VERSION 5.8 ;
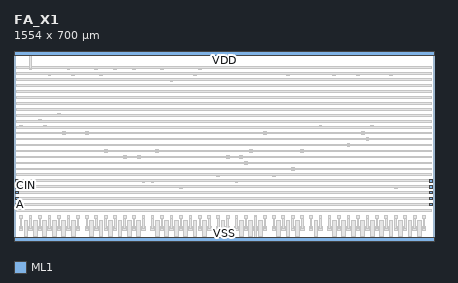
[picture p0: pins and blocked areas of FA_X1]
MACRO FA_X1
  CLASS CORE ;
  ORIGIN 0 0 ;
  SIZE 1554 BY 700 ;
  SITE ICPS2023_5_ROW700 ;
  PIN A
    DIRECTION INPUT ;
    USE SIGNAL ;
    PORT
      LAYER ML1 ;
        RECT 5 130 15 140 ;
        RECT 1539 130 1549 140 ;
    END
  END A
  PIN B
    DIRECTION INPUT ;
    USE SIGNAL ;
    PORT
      LAYER ML1 ;
        RECT 5 152 15 162 ;
        RECT 1539 152 1549 162 ;
    END
  END B
  PIN CIN
    DIRECTION INPUT ;
    USE SIGNAL ;
    PORT
      LAYER ML1 ;
        RECT 5 174 15 184 ;
        RECT 1539 174 1549 184 ;
    END
  END CIN
  PIN SUM
    DIRECTION OUTPUT ;
    USE SIGNAL ;
    PORT
      LAYER ML1 ;
        RECT 5 196 15 206 ;
        RECT 1539 196 1549 206 ;
    END
  END SUM
  PIN COUT
    DIRECTION OUTPUT ;
    USE SIGNAL ;
    PORT
      LAYER ML1 ;
        RECT 5 218 15 228 ;
        RECT 1539 218 1549 228 ;
    END
  END COUT
  PIN VDD
    DIRECTION INOUT ;
    USE POWER ;
    PORT
      LAYER ML1 ;
        RECT 0 688 1554 700 ;
    END
  END VDD
  PIN VSS
    DIRECTION INOUT ;
    USE GROUND ;
    PORT
      LAYER ML1 ;
        RECT 0 0 1554 12 ;
    END
  END VSS
  OBS
    LAYER ML1 ;
      RECT 20 39.5 33 52.5 ;
      RECT 55 39.5 68 52.5 ;
      RECT 90 39.5 103 52.5 ;
      RECT 125 39.5 138 52.5 ;
      RECT 160 39.5 173 52.5 ;
      RECT 195 39.5 208 52.5 ;
      RECT 230 39.5 243 52.5 ;
      RECT 37.5 16 50.5 29 ;
      RECT 37.5 63 50.5 76 ;
      RECT 37 16 51 76 ;
      RECT 72.5 16 85.5 29 ;
      RECT 72.5 63 85.5 76 ;
      RECT 72 16 86 76 ;
      RECT 107.5 16 120.5 29 ;
      RECT 107.5 63 120.5 76 ;
      RECT 107 16 121 76 ;
      RECT 142.5 16 155.5 29 ;
      RECT 142.5 63 155.5 76 ;
      RECT 142 16 156 76 ;
      RECT 177.5 16 190.5 29 ;
      RECT 177.5 63 190.5 76 ;
      RECT 177 16 191 76 ;
      RECT 212.5 16 225.5 29 ;
      RECT 212.5 63 225.5 76 ;
      RECT 212 16 226 76 ;
      RECT 23.5 46 29.5 89 ;
      RECT 21.5 84 31.5 94 ;
      RECT 21.5 416 31.5 426 ;
      RECT 58.5 46 64.5 89 ;
      RECT 56.5 84 66.5 94 ;
      RECT 56.5 636 66.5 646 ;
      RECT 93.5 46 99.5 89 ;
      RECT 91.5 84 101.5 94 ;
      RECT 91.5 438 101.5 448 ;
      RECT 128.5 46 134.5 89 ;
      RECT 126.5 84 136.5 94 ;
      RECT 126.5 614 136.5 624 ;
      RECT 163.5 46 169.5 89 ;
      RECT 161.5 84 171.5 94 ;
      RECT 161.5 460 171.5 470 ;
      RECT 198.5 46 204.5 89 ;
      RECT 196.5 84 206.5 94 ;
      RECT 196.5 636 206.5 646 ;
      RECT 233.5 46 239.5 89 ;
      RECT 231.5 84 241.5 94 ;
      RECT 231.5 526 241.5 536 ;
      RECT 39 152 49 162 ;
      RECT 74 130 84 140 ;
      RECT 109 416 119 426 ;
      RECT 144 152 154 162 ;
      RECT 179 394 189 404 ;
      RECT 214 614 224 624 ;
      RECT 263 39.5 276 52.5 ;
      RECT 298 39.5 311 52.5 ;
      RECT 333 39.5 346 52.5 ;
      RECT 368 39.5 381 52.5 ;
      RECT 403 39.5 416 52.5 ;
      RECT 438 39.5 451 52.5 ;
      RECT 473 39.5 486 52.5 ;
      RECT 280.5 16 293.5 29 ;
      RECT 280.5 63 293.5 76 ;
      RECT 280 16 294 76 ;
      RECT 315.5 16 328.5 29 ;
      RECT 315.5 63 328.5 76 ;
      RECT 315 16 329 76 ;
      RECT 350.5 16 363.5 29 ;
      RECT 350.5 63 363.5 76 ;
      RECT 350 16 364 76 ;
      RECT 385.5 16 398.5 29 ;
      RECT 385.5 63 398.5 76 ;
      RECT 385 16 399 76 ;
      RECT 420.5 16 433.5 29 ;
      RECT 420.5 63 433.5 76 ;
      RECT 420 16 434 76 ;
      RECT 455.5 16 468.5 29 ;
      RECT 455.5 63 468.5 76 ;
      RECT 455 16 469 76 ;
      RECT 266.5 46 272.5 89 ;
      RECT 264.5 84 274.5 94 ;
      RECT 264.5 394 274.5 404 ;
      RECT 301.5 46 307.5 89 ;
      RECT 299.5 84 309.5 94 ;
      RECT 299.5 636 309.5 646 ;
      RECT 336.5 46 342.5 89 ;
      RECT 334.5 84 344.5 94 ;
      RECT 334.5 328 344.5 338 ;
      RECT 371.5 46 377.5 89 ;
      RECT 369.5 84 379.5 94 ;
      RECT 369.5 636 379.5 646 ;
      RECT 406.5 46 412.5 89 ;
      RECT 404.5 84 414.5 94 ;
      RECT 404.5 306 414.5 316 ;
      RECT 441.5 46 447.5 89 ;
      RECT 439.5 84 449.5 94 ;
      RECT 439.5 636 449.5 646 ;
      RECT 476.5 46 482.5 89 ;
      RECT 474.5 84 484.5 94 ;
      RECT 474.5 218 484.5 228 ;
      RECT 282 130 292 140 ;
      RECT 317 614 327 624 ;
      RECT 352 174 362 184 ;
      RECT 387 152 397 162 ;
      RECT 422 130 432 140 ;
      RECT 457 306 467 316 ;
      RECT 506 39.5 519 52.5 ;
      RECT 541 39.5 554 52.5 ;
      RECT 576 39.5 589 52.5 ;
      RECT 611 39.5 624 52.5 ;
      RECT 646 39.5 659 52.5 ;
      RECT 681 39.5 694 52.5 ;
      RECT 716 39.5 729 52.5 ;
      RECT 523.5 16 536.5 29 ;
      RECT 523.5 63 536.5 76 ;
      RECT 523 16 537 76 ;
      RECT 558.5 16 571.5 29 ;
      RECT 558.5 63 571.5 76 ;
      RECT 558 16 572 76 ;
      RECT 593.5 16 606.5 29 ;
      RECT 593.5 63 606.5 76 ;
      RECT 593 16 607 76 ;
      RECT 628.5 16 641.5 29 ;
      RECT 628.5 63 641.5 76 ;
      RECT 628 16 642 76 ;
      RECT 663.5 16 676.5 29 ;
      RECT 663.5 63 676.5 76 ;
      RECT 663 16 677 76 ;
      RECT 698.5 16 711.5 29 ;
      RECT 698.5 63 711.5 76 ;
      RECT 698 16 712 76 ;
      RECT 509.5 46 515.5 89 ;
      RECT 507.5 84 517.5 94 ;
      RECT 507.5 218 517.5 228 ;
      RECT 544.5 46 550.5 89 ;
      RECT 542.5 84 552.5 94 ;
      RECT 542.5 636 552.5 646 ;
      RECT 579.5 46 585.5 89 ;
      RECT 577.5 84 587.5 94 ;
      RECT 577.5 592 587.5 602 ;
      RECT 614.5 46 620.5 89 ;
      RECT 612.5 84 622.5 94 ;
      RECT 612.5 196 622.5 206 ;
      RECT 649.5 46 655.5 89 ;
      RECT 647.5 84 657.5 94 ;
      RECT 647.5 570 657.5 580 ;
      RECT 684.5 46 690.5 89 ;
      RECT 682.5 84 692.5 94 ;
      RECT 682.5 636 692.5 646 ;
      RECT 719.5 46 725.5 89 ;
      RECT 717.5 84 727.5 94 ;
      RECT 717.5 548 727.5 558 ;
      RECT 525 328 535 338 ;
      RECT 560 526 570 536 ;
      RECT 595 174 605 184 ;
      RECT 630 548 640 558 ;
      RECT 665 614 675 624 ;
      RECT 700 174 710 184 ;
      RECT 749 39.5 762 52.5 ;
      RECT 784 39.5 797 52.5 ;
      RECT 766.5 16 779.5 29 ;
      RECT 766.5 63 779.5 76 ;
      RECT 766 16 780 76 ;
      RECT 752.5 46 758.5 89 ;
      RECT 750.5 84 760.5 94 ;
      RECT 750.5 240 760.5 250 ;
      RECT 787.5 46 793.5 89 ;
      RECT 785.5 84 795.5 94 ;
      RECT 785.5 306 795.5 316 ;
      RECT 768 130 778 140 ;
      RECT 817 39.5 830 52.5 ;
      RECT 852 39.5 865 52.5 ;
      RECT 887 39.5 900 52.5 ;
      RECT 922 39.5 935 52.5 ;
      RECT 834.5 16 847.5 29 ;
      RECT 834.5 63 847.5 76 ;
      RECT 834 16 848 76 ;
      RECT 869.5 16 882.5 29 ;
      RECT 869.5 63 882.5 76 ;
      RECT 869 16 883 76 ;
      RECT 904.5 16 917.5 29 ;
      RECT 904.5 63 917.5 76 ;
      RECT 904 16 918 76 ;
      RECT 820.5 46 826.5 89 ;
      RECT 818.5 84 828.5 94 ;
      RECT 818.5 218 828.5 228 ;
      RECT 855.5 46 861.5 89 ;
      RECT 853.5 84 863.5 94 ;
      RECT 853.5 284 863.5 294 ;
      RECT 890.5 46 896.5 89 ;
      RECT 888.5 84 898.5 94 ;
      RECT 888.5 108 898.5 118 ;
      RECT 925.5 46 931.5 89 ;
      RECT 923.5 84 933.5 94 ;
      RECT 923.5 394 933.5 404 ;
      RECT 836 306 846 316 ;
      RECT 871 328 881 338 ;
      RECT 906 130 916 140 ;
      RECT 955 39.5 968 52.5 ;
      RECT 990 39.5 1003 52.5 ;
      RECT 1025 39.5 1038 52.5 ;
      RECT 1060 39.5 1073 52.5 ;
      RECT 972.5 16 985.5 29 ;
      RECT 972.5 63 985.5 76 ;
      RECT 972 16 986 76 ;
      RECT 1007.5 16 1020.5 29 ;
      RECT 1007.5 63 1020.5 76 ;
      RECT 1007 16 1021 76 ;
      RECT 1042.5 16 1055.5 29 ;
      RECT 1042.5 63 1055.5 76 ;
      RECT 1042 16 1056 76 ;
      RECT 958.5 46 964.5 89 ;
      RECT 956.5 84 966.5 94 ;
      RECT 956.5 240 966.5 250 ;
      RECT 993.5 46 999.5 89 ;
      RECT 991.5 84 1001.5 94 ;
      RECT 991.5 108 1001.5 118 ;
      RECT 1028.5 46 1034.5 89 ;
      RECT 1026.5 84 1036.5 94 ;
      RECT 1026.5 262 1036.5 272 ;
      RECT 1063.5 46 1069.5 89 ;
      RECT 1061.5 84 1071.5 94 ;
      RECT 1061.5 328 1071.5 338 ;
      RECT 974 152 984 162 ;
      RECT 1009 614 1019 624 ;
      RECT 1044 174 1054 184 ;
      RECT 1093 39.5 1106 52.5 ;
      RECT 1128 39.5 1141 52.5 ;
      RECT 1110.5 16 1123.5 29 ;
      RECT 1110.5 63 1123.5 76 ;
      RECT 1110 16 1124 76 ;
      RECT 1096.5 46 1102.5 89 ;
      RECT 1094.5 84 1104.5 94 ;
      RECT 1094.5 108 1104.5 118 ;
      RECT 1131.5 46 1137.5 89 ;
      RECT 1129.5 84 1139.5 94 ;
      RECT 1129.5 416 1139.5 426 ;
      RECT 1112 152 1122 162 ;
      RECT 1161 39.5 1174 52.5 ;
      RECT 1196 39.5 1209 52.5 ;
      RECT 1231 39.5 1244 52.5 ;
      RECT 1266 39.5 1279 52.5 ;
      RECT 1301 39.5 1314 52.5 ;
      RECT 1336 39.5 1349 52.5 ;
      RECT 1371 39.5 1384 52.5 ;
      RECT 1406 39.5 1419 52.5 ;
      RECT 1441 39.5 1454 52.5 ;
      RECT 1476 39.5 1489 52.5 ;
      RECT 1511 39.5 1524 52.5 ;
      RECT 1178.5 16 1191.5 29 ;
      RECT 1178.5 63 1191.5 76 ;
      RECT 1178 16 1192 76 ;
      RECT 1213.5 16 1226.5 29 ;
      RECT 1213.5 63 1226.5 76 ;
      RECT 1213 16 1227 76 ;
      RECT 1248.5 16 1261.5 29 ;
      RECT 1248.5 63 1261.5 76 ;
      RECT 1248 16 1262 76 ;
      RECT 1283.5 16 1296.5 29 ;
      RECT 1283.5 63 1296.5 76 ;
      RECT 1283 16 1297 76 ;
      RECT 1318.5 16 1331.5 29 ;
      RECT 1318.5 63 1331.5 76 ;
      RECT 1318 16 1332 76 ;
      RECT 1353.5 16 1366.5 29 ;
      RECT 1353.5 63 1366.5 76 ;
      RECT 1353 16 1367 76 ;
      RECT 1388.5 16 1401.5 29 ;
      RECT 1388.5 63 1401.5 76 ;
      RECT 1388 16 1402 76 ;
      RECT 1423.5 16 1436.5 29 ;
      RECT 1423.5 63 1436.5 76 ;
      RECT 1423 16 1437 76 ;
      RECT 1458.5 16 1471.5 29 ;
      RECT 1458.5 63 1471.5 76 ;
      RECT 1458 16 1472 76 ;
      RECT 1493.5 16 1506.5 29 ;
      RECT 1493.5 63 1506.5 76 ;
      RECT 1493 16 1507 76 ;
      RECT 1164.5 46 1170.5 89 ;
      RECT 1162.5 84 1172.5 94 ;
      RECT 1162.5 526 1172.5 536 ;
      RECT 1199.5 46 1205.5 89 ;
      RECT 1197.5 84 1207.5 94 ;
      RECT 1197.5 108 1207.5 118 ;
      RECT 1234.5 46 1240.5 89 ;
      RECT 1232.5 84 1242.5 94 ;
      RECT 1232.5 350 1242.5 360 ;
      RECT 1269.5 46 1275.5 89 ;
      RECT 1267.5 84 1277.5 94 ;
      RECT 1267.5 614 1277.5 624 ;
      RECT 1304.5 46 1310.5 89 ;
      RECT 1302.5 84 1312.5 94 ;
      RECT 1302.5 372 1312.5 382 ;
      RECT 1339.5 46 1345.5 89 ;
      RECT 1337.5 84 1347.5 94 ;
      RECT 1337.5 108 1347.5 118 ;
      RECT 1374.5 46 1380.5 89 ;
      RECT 1372.5 84 1382.5 94 ;
      RECT 1372.5 482 1382.5 492 ;
      RECT 1409.5 46 1415.5 89 ;
      RECT 1407.5 84 1417.5 94 ;
      RECT 1407.5 196 1417.5 206 ;
      RECT 1444.5 46 1450.5 89 ;
      RECT 1442.5 84 1452.5 94 ;
      RECT 1442.5 504 1452.5 514 ;
      RECT 1479.5 46 1485.5 89 ;
      RECT 1477.5 84 1487.5 94 ;
      RECT 1477.5 108 1487.5 118 ;
      RECT 1514.5 46 1520.5 89 ;
      RECT 1512.5 84 1522.5 94 ;
      RECT 1512.5 548 1522.5 558 ;
      RECT 1180 614 1190 624 ;
      RECT 1215 152 1225 162 ;
      RECT 1250 130 1260 140 ;
      RECT 1285 394 1295 404 ;
      RECT 1320 416 1330 426 ;
      RECT 1355 174 1365 184 ;
      RECT 1390 614 1400 624 ;
      RECT 1425 526 1435 536 ;
      RECT 1460 548 1470 558 ;
      RECT 1495 174 1505 184 ;
      RECT 10 110 1544 116 ;
      RECT 10 132 1544 138 ;
      RECT 10 154 1544 160 ;
      RECT 10 176 1544 182 ;
      RECT 10 198 1544 204 ;
      RECT 10 220 1544 226 ;
      RECT 10 242 1544 248 ;
      RECT 10 264 1544 270 ;
      RECT 10 286 1544 292 ;
      RECT 10 308 1544 314 ;
      RECT 10 330 1544 336 ;
      RECT 10 352 1544 358 ;
      RECT 10 374 1544 380 ;
      RECT 10 396 1544 402 ;
      RECT 10 418 1544 424 ;
      RECT 10 440 1544 446 ;
      RECT 10 462 1544 468 ;
      RECT 10 484 1544 490 ;
      RECT 10 506 1544 512 ;
      RECT 10 528 1544 534 ;
      RECT 10 550 1544 556 ;
      RECT 10 572 1544 578 ;
      RECT 10 594 1544 600 ;
      RECT 10 616 1544 622 ;
      RECT 10 638 1544 644 ;
      RECT 890.5 3 896.5 92 ;
      RECT 58.5 638 64.5 697 ;
  END
END FA_X1
